VERSION 5.7 ;
  NOWIREEXTENSIONATPIN ON ;
  DIVIDERCHAR "/" ;
  BUSBITCHARS "[]" ;
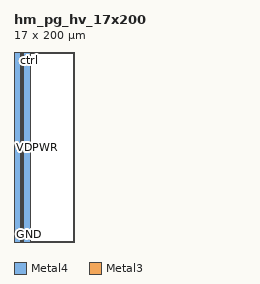
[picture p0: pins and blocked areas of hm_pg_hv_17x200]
MACRO hm_pg_hv_17x200
  CLASS BLOCK ;
  FOREIGN hm_pg_hv_17x200 ;
  ORIGIN 0.000 0.000 ;
  SIZE 17.000 BY 200.000 ;
  PIN VAPWR
    DIRECTION INOUT ;
    USE POWER ;
    PORT
      LAYER Metal4 ;
        RECT 0.000 0.000 7.000 200.000 ;
    END
  END VAPWR
  PIN VDPWR
    DIRECTION INOUT ;
    USE POWER ;
    PORT
      LAYER Metal4 ;
        RECT 8.650 0.000 9.700 200.000 ;
    END
  END VDPWR
  PIN GPWR
    ANTENNADIFFAREA 590.429199 ;
    PORT
      LAYER Metal4 ;
        RECT 10.000 0.000 17.000 200.000 ;
    END
  END GPWR
  PIN GND
    DIRECTION INPUT ;
    USE SIGNAL ;
    ANTENNADIFFAREA 25.435200 ;
    PORT
      LAYER Metal4 ;
        RECT 7.300 0.000 8.350 200.000 ;
    END
  END GND
  PIN ctrl
    ANTENNAGATEAREA 0.390000 ;
    PORT
      LAYER Metal3 ;
        RECT 14.600 199.580 17.000 200.000 ;
    END
  END ctrl
  OBS
      LAYER GatPoly ;
        RECT 0.030 0.240 16.760 198.220 ;
      LAYER Metal1 ;
        RECT 0.000 0.240 17.000 198.730 ;
      LAYER Metal2 ;
        RECT 0.000 1.480 17.000 200.000 ;
      LAYER Metal3 ;
        RECT 0.000 0.000 17.000 198.300 ;
  END
END hm_pg_hv_17x200
END LIBRARY

